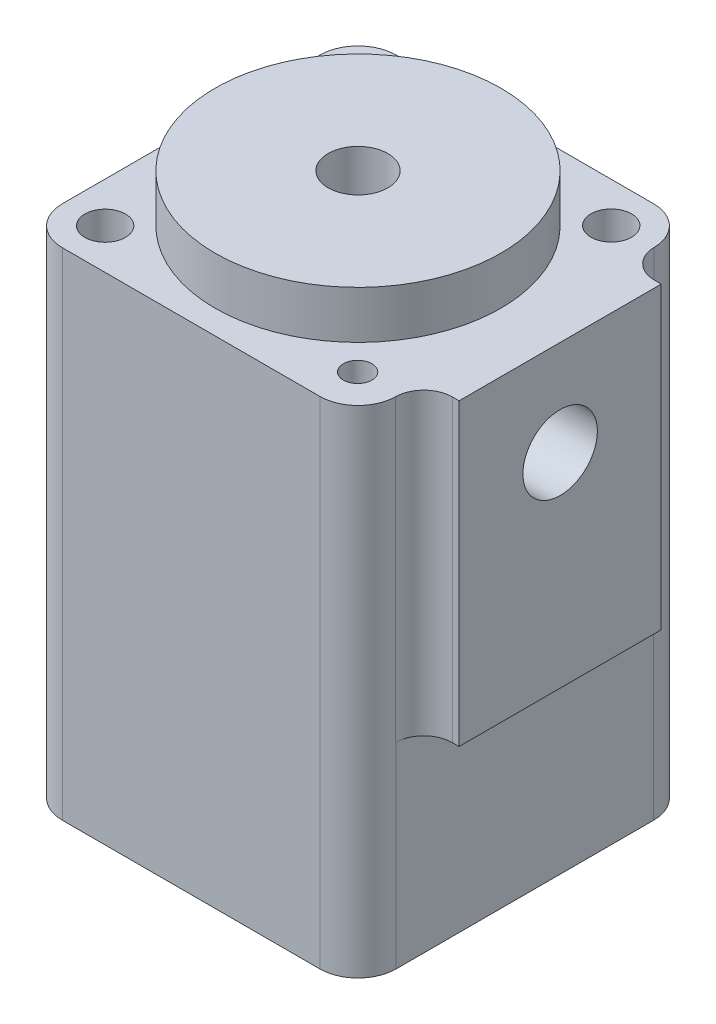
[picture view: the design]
ISO-10303-21;
HEADER;
FILE_DESCRIPTION(('STEP AP214'),'2;1');
FILE_NAME('part.step','',(''),(''),'','','');
FILE_SCHEMA(('AUTOMOTIVE_DESIGN { 1 0 10303 214 1 1 1 1 }'));
ENDSEC;
DATA;
#1=APPLICATION_CONTEXT('core data for automotive mechanical design processes');
#2=APPLICATION_PROTOCOL_DEFINITION('international standard','automotive_design',2000,#1);
#3=PRODUCT_CONTEXT('',#1,'mechanical');
#4=PRODUCT('Part','Part','',(#3));
#5=PRODUCT_RELATED_PRODUCT_CATEGORY('part','',(#4));
#6=PRODUCT_DEFINITION_FORMATION('','',#4);
#7=PRODUCT_DEFINITION_CONTEXT('part definition',#1,'design');
#8=PRODUCT_DEFINITION('design','',#6,#7);
#9=PRODUCT_DEFINITION_SHAPE('','',#8);
#10=(LENGTH_UNIT() NAMED_UNIT(*) SI_UNIT(.MILLI.,.METRE.));
#11=(NAMED_UNIT(*) PLANE_ANGLE_UNIT() SI_UNIT($,.RADIAN.));
#12=(NAMED_UNIT(*) SI_UNIT($,.STERADIAN.) SOLID_ANGLE_UNIT());
#13=UNCERTAINTY_MEASURE_WITH_UNIT(LENGTH_MEASURE(1.E-05),#10,'distance_accuracy_value','');
#14=(GEOMETRIC_REPRESENTATION_CONTEXT(3) GLOBAL_UNCERTAINTY_ASSIGNED_CONTEXT((#13)) GLOBAL_UNIT_ASSIGNED_CONTEXT((#10,
#11,#12)) REPRESENTATION_CONTEXT('',''));
#15=CARTESIAN_POINT('',(0.,0.,0.));
#16=DIRECTION('',(0.,0.,1.));
#17=DIRECTION('',(1.,0.,0.));
#18=AXIS2_PLACEMENT_3D('',#15,#16,#17);
#19=CARTESIAN_POINT('',(22.225,66.04,-22.225));
#20=DIRECTION('',(0.,-1.,0.));
#21=DIRECTION('',(0.,0.,-1.));
#22=AXIS2_PLACEMENT_3D('',#19,#20,#21);
#23=PLANE('',#22);
#24=CARTESIAN_POINT('',(16.8402,66.04,-16.8867242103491));
#25=DIRECTION('',(0.,1.,0.));
#26=DIRECTION('',(0.,0.,1.));
#27=AXIS2_PLACEMENT_3D('',#24,#25,#26);
#28=CIRCLE('',#27,2.70509999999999);
#29=CARTESIAN_POINT('',(16.8402,66.04,-14.1816242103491));
#30=VERTEX_POINT('',#29);
#31=EDGE_CURVE('E234',#30,#30,#28,.T.);
#32=ORIENTED_EDGE('',*,*,#31,.F.);
#33=EDGE_LOOP('',(#32));
#34=FACE_BOUND('',#33,.T.);
#35=CARTESIAN_POINT('',(-16.8402,66.04,16.8353752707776));
#36=DIRECTION('',(0.,1.,0.));
#37=DIRECTION('',(0.,0.,1.));
#38=AXIS2_PLACEMENT_3D('',#35,#36,#37);
#39=CIRCLE('',#38,2.70509999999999);
#40=CARTESIAN_POINT('',(-16.8402,66.04,19.5404752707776));
#41=VERTEX_POINT('',#40);
#42=EDGE_CURVE('E240',#41,#41,#39,.T.);
#43=ORIENTED_EDGE('',*,*,#42,.F.);
#44=EDGE_LOOP('',(#43));
#45=FACE_BOUND('',#44,.T.);
#46=CARTESIAN_POINT('',(-16.8402,66.04,-16.8353752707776));
#47=DIRECTION('',(0.,1.,0.));
#48=DIRECTION('',(0.,0.,1.));
#49=AXIS2_PLACEMENT_3D('',#46,#47,#48);
#50=CIRCLE('',#49,1.89864999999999);
#51=CARTESIAN_POINT('',(-16.8402,66.04,-14.9367252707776));
#52=VERTEX_POINT('',#51);
#53=EDGE_CURVE('E246',#52,#52,#50,.T.);
#54=ORIENTED_EDGE('',*,*,#53,.F.);
#55=EDGE_LOOP('',(#54));
#56=FACE_BOUND('',#55,.T.);
#57=CARTESIAN_POINT('',(16.8402,66.04,16.8867242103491));
#58=DIRECTION('',(0.,1.,0.));
#59=DIRECTION('',(0.,0.,1.));
#60=AXIS2_PLACEMENT_3D('',#57,#58,#59);
#61=CIRCLE('',#60,1.89864999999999);
#62=CARTESIAN_POINT('',(16.8402,66.04,18.7853742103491));
#63=VERTEX_POINT('',#62);
#64=EDGE_CURVE('E252',#63,#63,#61,.T.);
#65=ORIENTED_EDGE('',*,*,#64,.F.);
#66=EDGE_LOOP('',(#65));
#67=FACE_BOUND('',#66,.T.);
#68=DIRECTION('',(-1.,0.,0.));
#69=VECTOR('',#68,1.);
#70=CARTESIAN_POINT('',(-22.225,66.04,-22.225));
#71=LINE('',#70,#69);
#72=CARTESIAN_POINT('',(17.145,66.04,-22.225));
#73=VERTEX_POINT('',#72);
#74=CARTESIAN_POINT('',(-17.145,66.04,-22.225));
#75=VERTEX_POINT('',#74);
#76=EDGE_CURVE('E296',#73,#75,#71,.T.);
#77=ORIENTED_EDGE('',*,*,#76,.T.);
#78=CARTESIAN_POINT('',(-17.145,66.04,-17.145));
#79=DIRECTION('',(0.,-1.,0.));
#80=DIRECTION('',(0.,0.,-1.));
#81=AXIS2_PLACEMENT_3D('',#78,#79,#80);
#82=CIRCLE('',#81,5.08);
#83=CARTESIAN_POINT('',(-22.225,66.04,-17.145));
#84=VERTEX_POINT('',#83);
#85=EDGE_CURVE('E344',#75,#84,#82,.F.);
#86=ORIENTED_EDGE('',*,*,#85,.T.);
#87=DIRECTION('',(0.,0.,1.));
#88=VECTOR('',#87,1.);
#89=CARTESIAN_POINT('',(-22.225,66.04,22.225));
#90=LINE('',#89,#88);
#91=CARTESIAN_POINT('',(-22.225,66.04,17.145));
#92=VERTEX_POINT('',#91);
#93=EDGE_CURVE('E299',#84,#92,#90,.T.);
#94=ORIENTED_EDGE('',*,*,#93,.T.);
#95=CARTESIAN_POINT('',(-17.145,66.04,17.145));
#96=DIRECTION('',(0.,-1.,0.));
#97=DIRECTION('',(0.,0.,-1.));
#98=AXIS2_PLACEMENT_3D('',#95,#96,#97);
#99=CIRCLE('',#98,5.08);
#100=CARTESIAN_POINT('',(-17.145,66.04,22.225));
#101=VERTEX_POINT('',#100);
#102=EDGE_CURVE('E342',#92,#101,#99,.F.);
#103=ORIENTED_EDGE('',*,*,#102,.T.);
#104=DIRECTION('',(1.,0.,0.));
#105=VECTOR('',#104,1.);
#106=CARTESIAN_POINT('',(-22.225,66.04,22.225));
#107=LINE('',#106,#105);
#108=CARTESIAN_POINT('',(17.145,66.04,22.225));
#109=VERTEX_POINT('',#108);
#110=EDGE_CURVE('E303',#101,#109,#107,.T.);
#111=ORIENTED_EDGE('',*,*,#110,.T.);
#112=CARTESIAN_POINT('',(17.145,66.04,17.145));
#113=DIRECTION('',(0.,-1.,0.));
#114=DIRECTION('',(0.,0.,-1.));
#115=AXIS2_PLACEMENT_3D('',#112,#113,#114);
#116=CIRCLE('',#115,5.08);
#117=CARTESIAN_POINT('',(22.224481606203,66.04,17.2175714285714));
#118=VERTEX_POINT('',#117);
#119=EDGE_CURVE('E337',#109,#118,#116,.F.);
#120=ORIENTED_EDGE('',*,*,#119,.T.);
#121=CARTESIAN_POINT('',(26.0340928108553,66.04,17.272));
#122=DIRECTION('',(0.,-1.,0.));
#123=DIRECTION('',(0.,0.,-1.));
#124=AXIS2_PLACEMENT_3D('',#121,#122,#123);
#125=CIRCLE('',#124,3.81);
#126=CARTESIAN_POINT('',(26.0340928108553,66.04,13.462));
#127=VERTEX_POINT('',#126);
#128=EDGE_CURVE('E373',#118,#127,#125,.T.);
#129=ORIENTED_EDGE('',*,*,#128,.T.);
#130=DIRECTION('',(1.,0.,0.));
#131=VECTOR('',#130,1.);
#132=CARTESIAN_POINT('',(26.924,66.04,13.462));
#133=LINE('',#132,#131);
#134=CARTESIAN_POINT('',(26.924,66.04,13.462));
#135=VERTEX_POINT('',#134);
#136=EDGE_CURVE('E275',#127,#135,#133,.T.);
#137=ORIENTED_EDGE('',*,*,#136,.T.);
#138=DIRECTION('',(0.,0.,-1.));
#139=VECTOR('',#138,1.);
#140=CARTESIAN_POINT('',(26.924,66.04,-13.462));
#141=LINE('',#140,#139);
#142=CARTESIAN_POINT('',(26.924,66.04,-13.462));
#143=VERTEX_POINT('',#142);
#144=EDGE_CURVE('E277',#135,#143,#141,.T.);
#145=ORIENTED_EDGE('',*,*,#144,.T.);
#146=DIRECTION('',(-1.,0.,0.));
#147=VECTOR('',#146,1.);
#148=CARTESIAN_POINT('',(22.225,66.04,-13.462));
#149=LINE('',#148,#147);
#150=CARTESIAN_POINT('',(26.0340928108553,66.04,-13.462));
#151=VERTEX_POINT('',#150);
#152=EDGE_CURVE('E266',#143,#151,#149,.T.);
#153=ORIENTED_EDGE('',*,*,#152,.T.);
#154=CARTESIAN_POINT('',(26.0340928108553,66.04,-17.272));
#155=DIRECTION('',(0.,-1.,0.));
#156=DIRECTION('',(0.,0.,-1.));
#157=AXIS2_PLACEMENT_3D('',#154,#155,#156);
#158=CIRCLE('',#157,3.81);
#159=CARTESIAN_POINT('',(22.224481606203,66.04,-17.2175714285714));
#160=VERTEX_POINT('',#159);
#161=EDGE_CURVE('E377',#151,#160,#158,.T.);
#162=ORIENTED_EDGE('',*,*,#161,.T.);
#163=CARTESIAN_POINT('',(17.145,66.04,-17.145));
#164=DIRECTION('',(0.,-1.,0.));
#165=DIRECTION('',(0.,0.,-1.));
#166=AXIS2_PLACEMENT_3D('',#163,#164,#165);
#167=CIRCLE('',#166,5.08);
#168=EDGE_CURVE('E340',#160,#73,#167,.F.);
#169=ORIENTED_EDGE('',*,*,#168,.T.);
#170=EDGE_LOOP('',(#77,#86,#94,#103,#111,#120,#129,#137,#145,#153,#162,#169));
#171=FACE_BOUND('',#170,.T.);
#172=CARTESIAN_POINT('',(0.,66.04,0.));
#173=DIRECTION('',(0.,-1.,0.));
#174=DIRECTION('',(0.,0.,-1.));
#175=AXIS2_PLACEMENT_3D('',#172,#173,#174);
#176=CIRCLE('',#175,19.0373);
#177=CARTESIAN_POINT('',(0.,66.04,-19.0373));
#178=VERTEX_POINT('',#177);
#179=EDGE_CURVE('E306',#178,#178,#176,.F.);
#180=ORIENTED_EDGE('',*,*,#179,.F.);
#181=EDGE_LOOP('',(#180));
#182=FACE_BOUND('',#181,.T.);
#183=ADVANCED_FACE('F36',(#34,#45,#56,#67,#171,#182),#23,.F.);
#184=CARTESIAN_POINT('',(22.225,66.04,22.225));
#185=DIRECTION('',(-1.,0.,0.));
#186=DIRECTION('',(0.,0.,1.));
#187=AXIS2_PLACEMENT_3D('',#184,#185,#186);
#188=PLANE('',#187);
#189=DIRECTION('',(0.,0.,1.));
#190=VECTOR('',#189,1.);
#191=CARTESIAN_POINT('',(22.225,26.162,-13.462));
#192=LINE('',#191,#190);
#193=CARTESIAN_POINT('',(22.225,26.162,-17.145));
#194=VERTEX_POINT('',#193);
#195=CARTESIAN_POINT('',(22.225,26.162,17.145));
#196=VERTEX_POINT('',#195);
#197=EDGE_CURVE('E263',#194,#196,#192,.T.);
#198=ORIENTED_EDGE('',*,*,#197,.T.);
#199=DIRECTION('',(0.,-1.,0.));
#200=VECTOR('',#199,1.);
#201=CARTESIAN_POINT('',(22.225,66.04,17.145));
#202=LINE('',#201,#200);
#203=CARTESIAN_POINT('',(22.225,0.,17.145));
#204=VERTEX_POINT('',#203);
#205=EDGE_CURVE('E351',#196,#204,#202,.T.);
#206=ORIENTED_EDGE('',*,*,#205,.T.);
#207=DIRECTION('',(0.,0.,-1.));
#208=VECTOR('',#207,1.);
#209=CARTESIAN_POINT('',(22.225,0.,22.225));
#210=LINE('',#209,#208);
#211=CARTESIAN_POINT('',(22.225,0.,-17.145));
#212=VERTEX_POINT('',#211);
#213=EDGE_CURVE('E295',#204,#212,#210,.T.);
#214=ORIENTED_EDGE('',*,*,#213,.T.);
#215=DIRECTION('',(0.,-1.,0.));
#216=VECTOR('',#215,1.);
#217=CARTESIAN_POINT('',(22.225,66.04,-17.145));
#218=LINE('',#217,#216);
#219=EDGE_CURVE('E353',#212,#194,#218,.F.);
#220=ORIENTED_EDGE('',*,*,#219,.T.);
#221=EDGE_LOOP('',(#198,#206,#214,#220));
#222=FACE_BOUND('',#221,.T.);
#223=ADVANCED_FACE('F437',(#222),#188,.F.);
#224=CARTESIAN_POINT('',(-22.225,66.04,-22.225));
#225=DIRECTION('',(0.,0.,1.));
#226=DIRECTION('',(1.,0.,0.));
#227=AXIS2_PLACEMENT_3D('',#224,#225,#226);
#228=PLANE('',#227);
#229=DIRECTION('',(-1.,0.,0.));
#230=VECTOR('',#229,1.);
#231=CARTESIAN_POINT('',(-22.225,0.,-22.225));
#232=LINE('',#231,#230);
#233=CARTESIAN_POINT('',(17.145,0.,-22.225));
#234=VERTEX_POINT('',#233);
#235=CARTESIAN_POINT('',(-17.145,0.,-22.225));
#236=VERTEX_POINT('',#235);
#237=EDGE_CURVE('E309',#234,#236,#232,.T.);
#238=ORIENTED_EDGE('',*,*,#237,.T.);
#239=DIRECTION('',(0.,-1.,0.));
#240=VECTOR('',#239,1.);
#241=CARTESIAN_POINT('',(-17.145,66.04,-22.225));
#242=LINE('',#241,#240);
#243=EDGE_CURVE('E335',#236,#75,#242,.F.);
#244=ORIENTED_EDGE('',*,*,#243,.T.);
#245=ORIENTED_EDGE('',*,*,#76,.F.);
#246=DIRECTION('',(0.,-1.,0.));
#247=VECTOR('',#246,1.);
#248=CARTESIAN_POINT('',(17.145,66.04,-22.225));
#249=LINE('',#248,#247);
#250=EDGE_CURVE('E332',#73,#234,#249,.T.);
#251=ORIENTED_EDGE('',*,*,#250,.T.);
#252=EDGE_LOOP('',(#238,#244,#245,#251));
#253=FACE_BOUND('',#252,.T.);
#254=ADVANCED_FACE('F443',(#253),#228,.F.);
#255=CARTESIAN_POINT('',(-22.225,66.04,22.225));
#256=DIRECTION('',(1.,0.,0.));
#257=DIRECTION('',(0.,0.,-1.));
#258=AXIS2_PLACEMENT_3D('',#255,#256,#257);
#259=PLANE('',#258);
#260=ORIENTED_EDGE('',*,*,#93,.F.);
#261=DIRECTION('',(0.,-1.,0.));
#262=VECTOR('',#261,1.);
#263=CARTESIAN_POINT('',(-22.225,66.04,-17.145));
#264=LINE('',#263,#262);
#265=CARTESIAN_POINT('',(-22.225,0.,-17.145));
#266=VERTEX_POINT('',#265);
#267=EDGE_CURVE('E321',#84,#266,#264,.T.);
#268=ORIENTED_EDGE('',*,*,#267,.T.);
#269=DIRECTION('',(0.,0.,1.));
#270=VECTOR('',#269,1.);
#271=CARTESIAN_POINT('',(-22.225,0.,22.225));
#272=LINE('',#271,#270);
#273=CARTESIAN_POINT('',(-22.225,0.,17.145));
#274=VERTEX_POINT('',#273);
#275=EDGE_CURVE('E312',#266,#274,#272,.T.);
#276=ORIENTED_EDGE('',*,*,#275,.T.);
#277=DIRECTION('',(0.,-1.,0.));
#278=VECTOR('',#277,1.);
#279=CARTESIAN_POINT('',(-22.225,66.04,17.145));
#280=LINE('',#279,#278);
#281=EDGE_CURVE('E319',#274,#92,#280,.F.);
#282=ORIENTED_EDGE('',*,*,#281,.T.);
#283=EDGE_LOOP('',(#260,#268,#276,#282));
#284=FACE_BOUND('',#283,.T.);
#285=ADVANCED_FACE('F458',(#284),#259,.F.);
#286=CARTESIAN_POINT('',(-22.225,66.04,22.225));
#287=DIRECTION('',(0.,0.,-1.));
#288=DIRECTION('',(-1.,0.,0.));
#289=AXIS2_PLACEMENT_3D('',#286,#287,#288);
#290=PLANE('',#289);
#291=ORIENTED_EDGE('',*,*,#110,.F.);
#292=DIRECTION('',(0.,-1.,0.));
#293=VECTOR('',#292,1.);
#294=CARTESIAN_POINT('',(-17.145,66.04,22.225));
#295=LINE('',#294,#293);
#296=CARTESIAN_POINT('',(-17.145,0.,22.225));
#297=VERTEX_POINT('',#296);
#298=EDGE_CURVE('E348',#101,#297,#295,.T.);
#299=ORIENTED_EDGE('',*,*,#298,.T.);
#300=DIRECTION('',(1.,0.,0.));
#301=VECTOR('',#300,1.);
#302=CARTESIAN_POINT('',(-22.225,0.,22.225));
#303=LINE('',#302,#301);
#304=CARTESIAN_POINT('',(17.145,0.,22.225));
#305=VERTEX_POINT('',#304);
#306=EDGE_CURVE('E300',#297,#305,#303,.T.);
#307=ORIENTED_EDGE('',*,*,#306,.T.);
#308=DIRECTION('',(0.,-1.,0.));
#309=VECTOR('',#308,1.);
#310=CARTESIAN_POINT('',(17.145,66.04,22.225));
#311=LINE('',#310,#309);
#312=EDGE_CURVE('E346',#305,#109,#311,.F.);
#313=ORIENTED_EDGE('',*,*,#312,.T.);
#314=EDGE_LOOP('',(#291,#299,#307,#313));
#315=FACE_BOUND('',#314,.T.);
#316=ADVANCED_FACE('F454',(#315),#290,.F.);
#317=CARTESIAN_POINT('',(22.225,0.,-22.225));
#318=DIRECTION('',(0.,-1.,0.));
#319=DIRECTION('',(0.,0.,-1.));
#320=AXIS2_PLACEMENT_3D('',#317,#318,#319);
#321=PLANE('',#320);
#322=CARTESIAN_POINT('',(0.,0.,-9.525));
#323=DIRECTION('',(0.,-1.,0.));
#324=DIRECTION('',(0.,0.,-1.));
#325=AXIS2_PLACEMENT_3D('',#322,#323,#324);
#326=CIRCLE('',#325,10.5);
#327=CARTESIAN_POINT('',(-4.41863949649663,0.,0.));
#328=VERTEX_POINT('',#327);
#329=CARTESIAN_POINT('',(4.41863949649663,0.,0.));
#330=VERTEX_POINT('',#329);
#331=EDGE_CURVE('E200',#328,#330,#326,.T.);
#332=ORIENTED_EDGE('',*,*,#331,.F.);
#333=CARTESIAN_POINT('',(0.,0.,9.525));
#334=DIRECTION('',(0.,-1.,0.));
#335=DIRECTION('',(0.,0.,-1.));
#336=AXIS2_PLACEMENT_3D('',#333,#334,#335);
#337=CIRCLE('',#336,10.5);
#338=EDGE_CURVE('E231',#330,#328,#337,.T.);
#339=ORIENTED_EDGE('',*,*,#338,.F.);
#340=EDGE_LOOP('',(#332,#339));
#341=FACE_BOUND('',#340,.T.);
#342=CARTESIAN_POINT('',(16.8402,0.,-16.8867242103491));
#343=DIRECTION('',(0.,1.,0.));
#344=DIRECTION('',(0.,0.,1.));
#345=AXIS2_PLACEMENT_3D('',#342,#343,#344);
#346=CIRCLE('',#345,2.70509999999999);
#347=CARTESIAN_POINT('',(16.8402,0.,-14.1816242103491));
#348=VERTEX_POINT('',#347);
#349=EDGE_CURVE('E237',#348,#348,#346,.T.);
#350=ORIENTED_EDGE('',*,*,#349,.T.);
#351=EDGE_LOOP('',(#350));
#352=FACE_BOUND('',#351,.T.);
#353=CARTESIAN_POINT('',(-16.8402,0.,16.8353752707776));
#354=DIRECTION('',(0.,1.,0.));
#355=DIRECTION('',(0.,0.,1.));
#356=AXIS2_PLACEMENT_3D('',#353,#354,#355);
#357=CIRCLE('',#356,2.70509999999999);
#358=CARTESIAN_POINT('',(-16.8402,0.,19.5404752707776));
#359=VERTEX_POINT('',#358);
#360=EDGE_CURVE('E243',#359,#359,#357,.T.);
#361=ORIENTED_EDGE('',*,*,#360,.T.);
#362=EDGE_LOOP('',(#361));
#363=FACE_BOUND('',#362,.T.);
#364=CARTESIAN_POINT('',(-16.8402,0.,-16.8353752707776));
#365=DIRECTION('',(0.,1.,0.));
#366=DIRECTION('',(0.,0.,1.));
#367=AXIS2_PLACEMENT_3D('',#364,#365,#366);
#368=CIRCLE('',#367,1.89864999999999);
#369=CARTESIAN_POINT('',(-16.8402,0.,-14.9367252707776));
#370=VERTEX_POINT('',#369);
#371=EDGE_CURVE('E249',#370,#370,#368,.T.);
#372=ORIENTED_EDGE('',*,*,#371,.T.);
#373=EDGE_LOOP('',(#372));
#374=FACE_BOUND('',#373,.T.);
#375=CARTESIAN_POINT('',(16.8402,0.,16.8867242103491));
#376=DIRECTION('',(0.,1.,0.));
#377=DIRECTION('',(0.,0.,1.));
#378=AXIS2_PLACEMENT_3D('',#375,#376,#377);
#379=CIRCLE('',#378,1.89864999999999);
#380=CARTESIAN_POINT('',(16.8402,0.,18.7853742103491));
#381=VERTEX_POINT('',#380);
#382=EDGE_CURVE('E255',#381,#381,#379,.T.);
#383=ORIENTED_EDGE('',*,*,#382,.T.);
#384=EDGE_LOOP('',(#383));
#385=FACE_BOUND('',#384,.T.);
#386=ORIENTED_EDGE('',*,*,#275,.F.);
#387=CARTESIAN_POINT('',(-17.145,0.,-17.145));
#388=DIRECTION('',(0.,-1.,0.));
#389=DIRECTION('',(0.,0.,-1.));
#390=AXIS2_PLACEMENT_3D('',#387,#388,#389);
#391=CIRCLE('',#390,5.08);
#392=EDGE_CURVE('E330',#266,#236,#391,.T.);
#393=ORIENTED_EDGE('',*,*,#392,.T.);
#394=ORIENTED_EDGE('',*,*,#237,.F.);
#395=CARTESIAN_POINT('',(17.145,0.,-17.145));
#396=DIRECTION('',(0.,-1.,0.));
#397=DIRECTION('',(0.,0.,-1.));
#398=AXIS2_PLACEMENT_3D('',#395,#396,#397);
#399=CIRCLE('',#398,5.08);
#400=EDGE_CURVE('E326',#234,#212,#399,.T.);
#401=ORIENTED_EDGE('',*,*,#400,.T.);
#402=ORIENTED_EDGE('',*,*,#213,.F.);
#403=CARTESIAN_POINT('',(17.145,0.,17.145));
#404=DIRECTION('',(0.,-1.,0.));
#405=DIRECTION('',(0.,0.,-1.));
#406=AXIS2_PLACEMENT_3D('',#403,#404,#405);
#407=CIRCLE('',#406,5.08);
#408=EDGE_CURVE('E324',#204,#305,#407,.T.);
#409=ORIENTED_EDGE('',*,*,#408,.T.);
#410=ORIENTED_EDGE('',*,*,#306,.F.);
#411=CARTESIAN_POINT('',(-17.145,0.,17.145));
#412=DIRECTION('',(0.,-1.,0.));
#413=DIRECTION('',(0.,0.,-1.));
#414=AXIS2_PLACEMENT_3D('',#411,#412,#413);
#415=CIRCLE('',#414,5.08);
#416=EDGE_CURVE('E328',#297,#274,#415,.T.);
#417=ORIENTED_EDGE('',*,*,#416,.T.);
#418=EDGE_LOOP('',(#386,#393,#394,#401,#402,#409,#410,#417));
#419=FACE_BOUND('',#418,.T.);
#420=ADVANCED_FACE('F451',(#341,#352,#363,#374,#385,#419),#321,.T.);
#421=CARTESIAN_POINT('',(0.,72.39,0.));
#422=DIRECTION('',(0.,-1.,0.));
#423=DIRECTION('',(0.,0.,-1.));
#424=AXIS2_PLACEMENT_3D('',#421,#422,#423);
#425=CYLINDRICAL_SURFACE('',#424,19.0373);
#426=CARTESIAN_POINT('',(0.,72.39,0.));
#427=DIRECTION('',(0.,1.,0.));
#428=DIRECTION('',(0.,0.,1.));
#429=AXIS2_PLACEMENT_3D('',#426,#427,#428);
#430=CIRCLE('',#429,19.0373);
#431=CARTESIAN_POINT('',(0.,72.39,19.0373));
#432=VERTEX_POINT('',#431);
#433=EDGE_CURVE('E290',#432,#432,#430,.T.);
#434=ORIENTED_EDGE('',*,*,#433,.F.);
#435=EDGE_LOOP('',(#434));
#436=FACE_BOUND('',#435,.T.);
#437=ORIENTED_EDGE('',*,*,#179,.T.);
#438=EDGE_LOOP('',(#437));
#439=FACE_BOUND('',#438,.T.);
#440=ADVANCED_FACE('F450',(#436,#439),#425,.T.);
#441=CARTESIAN_POINT('',(0.,72.39,0.));
#442=DIRECTION('',(0.,1.,0.));
#443=DIRECTION('',(0.,0.,1.));
#444=AXIS2_PLACEMENT_3D('',#441,#442,#443);
#445=PLANE('',#444);
#446=CARTESIAN_POINT('',(0.,72.39,0.));
#447=DIRECTION('',(0.,1.,0.));
#448=DIRECTION('',(0.,0.,1.));
#449=AXIS2_PLACEMENT_3D('',#446,#447,#448);
#450=CIRCLE('',#449,3.96875);
#451=CARTESIAN_POINT('',(0.,72.39,3.96875));
#452=VERTEX_POINT('',#451);
#453=EDGE_CURVE('E284',#452,#452,#450,.T.);
#454=ORIENTED_EDGE('',*,*,#453,.F.);
#455=EDGE_LOOP('',(#454));
#456=FACE_BOUND('',#455,.T.);
#457=ORIENTED_EDGE('',*,*,#433,.T.);
#458=EDGE_LOOP('',(#457));
#459=FACE_BOUND('',#458,.T.);
#460=ADVANCED_FACE('F434',(#456,#459),#445,.T.);
#461=CARTESIAN_POINT('',(0.,34.29,0.));
#462=DIRECTION('',(0.,1.,0.));
#463=DIRECTION('',(0.,0.,1.));
#464=AXIS2_PLACEMENT_3D('',#461,#462,#463);
#465=CYLINDRICAL_SURFACE('',#464,3.96875);
#466=DIRECTION('',(0.,1.,0.));
#467=VECTOR('',#466,1.);
#468=CARTESIAN_POINT('',(0.761999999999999,34.29,-3.89491111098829));
#469=LINE('',#468,#467);
#470=CARTESIAN_POINT('',(0.761999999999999,50.2679618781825,-3.89491111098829));
#471=VERTEX_POINT('',#470);
#472=CARTESIAN_POINT('',(0.761999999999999,56.4120381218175,-3.89491111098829));
#473=VERTEX_POINT('',#472);
#474=EDGE_CURVE('E387',#471,#473,#469,.T.);
#475=ORIENTED_EDGE('',*,*,#474,.T.);
#476=CARTESIAN_POINT('',(0.761999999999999,56.4120381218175,-3.89491111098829));
#477=CARTESIAN_POINT('',(0.872602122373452,56.4394920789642,-3.87326278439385));
#478=CARTESIAN_POINT('',(0.980867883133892,56.4719380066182,-3.84720182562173));
#479=CARTESIAN_POINT('',(1.19218803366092,56.5444070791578,-3.78704563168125));
#480=CARTESIAN_POINT('',(1.29525636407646,56.5844084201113,-3.75297344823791));
#481=CARTESIAN_POINT('',(1.49566621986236,56.6695055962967,-3.67768316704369));
#482=CARTESIAN_POINT('',(1.5930386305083,56.7145691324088,-3.63650956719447));
#483=CARTESIAN_POINT('',(1.78287873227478,56.808231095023,-3.54729779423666));
#484=CARTESIAN_POINT('',(1.87534246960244,56.8568322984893,-3.49925419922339));
#485=CARTESIAN_POINT('',(2.14346593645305,57.0045588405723,-3.34643132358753));
#486=CARTESIAN_POINT('',(2.31214160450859,57.1066517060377,-3.2320830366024));
#487=CARTESIAN_POINT('',(2.63072429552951,57.3102094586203,-2.97855163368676));
#488=CARTESIAN_POINT('',(2.78058879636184,57.4116724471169,-2.83931391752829));
#489=CARTESIAN_POINT('',(3.06070716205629,57.6078620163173,-2.53499263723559));
#490=CARTESIAN_POINT('',(3.19076478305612,57.7025168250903,-2.36967981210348));
#491=CARTESIAN_POINT('',(3.4256245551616,57.8771294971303,-2.01521458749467));
#492=CARTESIAN_POINT('',(3.53047206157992,57.9571136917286,-1.82610594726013));
#493=CARTESIAN_POINT('',(3.69375347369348,58.0832505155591,-1.4626661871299));
#494=CARTESIAN_POINT('',(3.75714272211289,58.1329001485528,-1.2917896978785));
#495=CARTESIAN_POINT('',(3.86044559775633,58.2142994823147,-0.938962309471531));
#496=CARTESIAN_POINT('',(3.90037223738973,58.2460591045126,-0.757017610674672));
#497=CARTESIAN_POINT('',(3.95439235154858,58.2891133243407,-0.386039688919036));
#498=CARTESIAN_POINT('',(3.96836910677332,58.3003154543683,-0.196978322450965));
#499=CARTESIAN_POINT('',(3.96911526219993,58.3009120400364,0.181225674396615));
#500=CARTESIAN_POINT('',(3.95588783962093,58.2903090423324,0.370368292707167));
#501=CARTESIAN_POINT('',(3.9051423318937,58.2498577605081,0.728854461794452));
#502=CARTESIAN_POINT('',(3.86946961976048,58.2214722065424,0.898634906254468));
#503=CARTESIAN_POINT('',(3.7775713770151,58.1489525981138,1.22896239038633));
#504=CARTESIAN_POINT('',(3.72134037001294,58.1048143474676,1.38950695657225));
#505=CARTESIAN_POINT('',(3.5858484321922,57.999733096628,1.71034193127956));
#506=CARTESIAN_POINT('',(3.50516429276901,57.9377694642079,1.86968958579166));
#507=CARTESIAN_POINT('',(3.32589301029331,57.802608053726,2.17265656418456));
#508=CARTESIAN_POINT('',(3.22730049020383,57.7294069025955,2.31627114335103));
#509=CARTESIAN_POINT('',(2.99373860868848,57.5603667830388,2.61361058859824));
#510=CARTESIAN_POINT('',(2.8554280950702,57.4629059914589,2.76377649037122));
#511=CARTESIAN_POINT('',(2.5590236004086,57.2634213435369,3.04032718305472));
#512=CARTESIAN_POINT('',(2.40088918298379,57.1613884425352,3.16666200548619));
#513=CARTESIAN_POINT('',(2.15139891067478,57.0116523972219,3.33651112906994));
#514=CARTESIAN_POINT('',(2.0670390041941,56.9627389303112,3.38944204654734));
#515=CARTESIAN_POINT('',(1.89374016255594,56.8667273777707,3.48923040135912));
#516=CARTESIAN_POINT('',(1.80480006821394,56.8196297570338,3.53608629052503));
#517=CARTESIAN_POINT('',(1.62270487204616,56.7287679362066,3.62325141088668));
#518=CARTESIAN_POINT('',(1.52957009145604,56.684989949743,3.66358860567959));
#519=CARTESIAN_POINT('',(1.33867874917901,56.6021235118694,3.73756365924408));
#520=CARTESIAN_POINT('',(1.24092477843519,56.563032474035,3.77120521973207));
#521=CARTESIAN_POINT('',(1.07945788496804,56.5052356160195,3.81966782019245));
#522=CARTESIAN_POINT('',(1.01715104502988,56.4844810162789,3.8367444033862));
#523=CARTESIAN_POINT('',(0.890820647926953,56.4459151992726,3.86803010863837));
#524=CARTESIAN_POINT('',(0.826794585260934,56.428108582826,3.88223475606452));
#525=CARTESIAN_POINT('',(0.761999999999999,56.4120381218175,3.89491111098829));
#526=B_SPLINE_CURVE_WITH_KNOTS('',3,(#476,#477,#478,#479,#480,#481,#482,#483,#484,#485,#486,
#487,#488,#489,#490,#491,#492,#493,#494,#495,#496,#497,#498,#499,#500,#501,#502,#503,#504,#505,
#506,#507,#508,#509,#510,#511,#512,#513,#514,#515,#516,#517,#518,#519,#520,#521,#522,#523,#524,
#525),.UNSPECIFIED.,.F.,.F.,(4,2,2,2,2,2,2,2,2,2,2,2,2,2,2,2,2,2,2,2,2,2,2,2,4),(0.,
0.34745550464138,0.693923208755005,1.0382939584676,1.38293800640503,2.06432483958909,
2.7472252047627,3.43650407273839,4.12453342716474,4.68887944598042,5.25291218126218,
5.819475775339,6.38597320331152,6.91108033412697,7.43632744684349,8.00141087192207,
8.56666424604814,9.24299422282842,9.92072692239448,10.2533741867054,10.5861060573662,
10.9173703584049,11.2484510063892,11.451886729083,11.6556370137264),.UNSPECIFIED.);
#527=CARTESIAN_POINT('',(0.761999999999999,56.4120381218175,3.89491111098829));
#528=VERTEX_POINT('',#527);
#529=EDGE_CURVE('E11',#473,#528,#526,.T.);
#530=ORIENTED_EDGE('',*,*,#529,.T.);
#531=DIRECTION('',(0.,1.,0.));
#532=VECTOR('',#531,1.);
#533=CARTESIAN_POINT('',(0.761999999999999,34.29,3.89491111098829));
#534=LINE('',#533,#532);
#535=CARTESIAN_POINT('',(0.761999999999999,50.2679618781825,3.89491111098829));
#536=VERTEX_POINT('',#535);
#537=EDGE_CURVE('E49',#528,#536,#534,.F.);
#538=ORIENTED_EDGE('',*,*,#537,.T.);
#539=CARTESIAN_POINT('',(0.761999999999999,50.2679618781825,3.89491111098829));
#540=CARTESIAN_POINT('',(0.872602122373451,50.2405079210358,3.87326278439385));
#541=CARTESIAN_POINT('',(0.98086788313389,50.2080619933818,3.84720182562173));
#542=CARTESIAN_POINT('',(1.19218803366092,50.1355929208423,3.78704563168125));
#543=CARTESIAN_POINT('',(1.29525636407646,50.0955915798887,3.75297344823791));
#544=CARTESIAN_POINT('',(1.49566621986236,50.0104944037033,3.6776831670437));
#545=CARTESIAN_POINT('',(1.5930386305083,49.9654308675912,3.63650956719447));
#546=CARTESIAN_POINT('',(1.78287873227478,49.871768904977,3.54729779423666));
#547=CARTESIAN_POINT('',(1.87534246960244,49.8231677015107,3.49925419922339));
#548=CARTESIAN_POINT('',(2.14346593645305,49.6754411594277,3.34643132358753));
#549=CARTESIAN_POINT('',(2.31214160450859,49.5733482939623,3.2320830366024));
#550=CARTESIAN_POINT('',(2.63072429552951,49.3697905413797,2.97855163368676));
#551=CARTESIAN_POINT('',(2.78058879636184,49.2683275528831,2.83931391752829));
#552=CARTESIAN_POINT('',(3.06070716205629,49.0721379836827,2.5349926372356));
#553=CARTESIAN_POINT('',(3.19076478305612,48.9774831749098,2.36967981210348));
#554=CARTESIAN_POINT('',(3.42562455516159,48.8028705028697,2.01521458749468));
#555=CARTESIAN_POINT('',(3.53047206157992,48.7228863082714,1.82610594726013));
#556=CARTESIAN_POINT('',(3.69375347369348,48.5967494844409,1.46266618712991));
#557=CARTESIAN_POINT('',(3.75714272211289,48.5470998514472,1.29178969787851));
#558=CARTESIAN_POINT('',(3.86044559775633,48.4657005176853,0.938962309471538));
#559=CARTESIAN_POINT('',(3.90037223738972,48.4339408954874,0.757017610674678));
#560=CARTESIAN_POINT('',(3.95439235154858,48.3908866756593,0.386039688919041));
#561=CARTESIAN_POINT('',(3.96836910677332,48.3796845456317,0.19697832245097));
#562=CARTESIAN_POINT('',(3.96911526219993,48.3790879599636,-0.18122567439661));
#563=CARTESIAN_POINT('',(3.95588783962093,48.3896909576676,-0.370368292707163));
#564=CARTESIAN_POINT('',(3.9051423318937,48.4301422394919,-0.728854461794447));
#565=CARTESIAN_POINT('',(3.86946961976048,48.4585277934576,-0.898634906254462));
#566=CARTESIAN_POINT('',(3.7775713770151,48.5310474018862,-1.22896239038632));
#567=CARTESIAN_POINT('',(3.72134037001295,48.5751856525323,-1.38950695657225));
#568=CARTESIAN_POINT('',(3.5858484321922,48.680266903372,-1.71034193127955));
#569=CARTESIAN_POINT('',(3.50516429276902,48.7422305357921,-1.86968958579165));
#570=CARTESIAN_POINT('',(3.32589301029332,48.877391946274,-2.17265656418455));
#571=CARTESIAN_POINT('',(3.22730049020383,48.9505930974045,-2.31627114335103));
#572=CARTESIAN_POINT('',(2.99373860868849,49.1196332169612,-2.61361058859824));
#573=CARTESIAN_POINT('',(2.85542809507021,49.2170940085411,-2.76377649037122));
#574=CARTESIAN_POINT('',(2.5590236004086,49.4165786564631,-3.04032718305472));
#575=CARTESIAN_POINT('',(2.4008891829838,49.5186115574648,-3.16666200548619));
#576=CARTESIAN_POINT('',(2.15139891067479,49.6683476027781,-3.33651112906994));
#577=CARTESIAN_POINT('',(2.0670390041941,49.7172610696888,-3.38944204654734));
#578=CARTESIAN_POINT('',(1.89374016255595,49.8132726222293,-3.48923040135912));
#579=CARTESIAN_POINT('',(1.80480006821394,49.8603702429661,-3.53608629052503));
#580=CARTESIAN_POINT('',(1.62270487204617,49.9512320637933,-3.62325141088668));
#581=CARTESIAN_POINT('',(1.52957009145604,49.995010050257,-3.66358860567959));
#582=CARTESIAN_POINT('',(1.33867874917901,50.0778764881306,-3.73756365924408));
#583=CARTESIAN_POINT('',(1.2409247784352,50.116967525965,-3.77120521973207));
#584=CARTESIAN_POINT('',(1.07945788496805,50.1747643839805,-3.81966782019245));
#585=CARTESIAN_POINT('',(1.01715104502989,50.1955189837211,-3.83674440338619));
#586=CARTESIAN_POINT('',(0.890820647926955,50.2340848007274,-3.86803010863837));
#587=CARTESIAN_POINT('',(0.826794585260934,50.251891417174,-3.88223475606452));
#588=CARTESIAN_POINT('',(0.761999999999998,50.2679618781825,-3.89491111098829));
#589=B_SPLINE_CURVE_WITH_KNOTS('',3,(#539,#540,#541,#542,#543,#544,#545,#546,#547,#548,#549,
#550,#551,#552,#553,#554,#555,#556,#557,#558,#559,#560,#561,#562,#563,#564,#565,#566,#567,#568,
#569,#570,#571,#572,#573,#574,#575,#576,#577,#578,#579,#580,#581,#582,#583,#584,#585,#586,#587,
#588),.UNSPECIFIED.,.F.,.F.,(4,2,2,2,2,2,2,2,2,2,2,2,2,2,2,2,2,2,2,2,2,2,2,2,4),(0.,
0.347455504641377,0.693923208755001,1.03829395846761,1.38293800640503,2.06432483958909,
2.7472252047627,3.43650407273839,4.12453342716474,4.68887944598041,5.25291218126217,
5.819475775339,6.38597320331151,6.91108033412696,7.43632744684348,8.00141087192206,
8.56666424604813,9.24299422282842,9.92072692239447,10.2533741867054,10.5861060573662,
10.9173703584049,11.2484510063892,11.451886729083,11.6556370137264),.UNSPECIFIED.);
#590=EDGE_CURVE('E381',#536,#471,#589,.T.);
#591=ORIENTED_EDGE('',*,*,#590,.T.);
#592=EDGE_LOOP('',(#475,#530,#538,#591));
#593=FACE_BOUND('',#592,.T.);
#594=CARTESIAN_POINT('',(0.,34.29,0.));
#595=DIRECTION('',(0.,1.,0.));
#596=DIRECTION('',(0.,0.,1.));
#597=AXIS2_PLACEMENT_3D('',#594,#595,#596);
#598=CIRCLE('',#597,3.96875);
#599=CARTESIAN_POINT('',(0.,34.29,3.96875));
#600=VERTEX_POINT('',#599);
#601=EDGE_CURVE('E287',#600,#600,#598,.T.);
#602=ORIENTED_EDGE('',*,*,#601,.F.);
#603=EDGE_LOOP('',(#602));
#604=FACE_BOUND('',#603,.T.);
#605=ORIENTED_EDGE('',*,*,#453,.T.);
#606=EDGE_LOOP('',(#605));
#607=FACE_BOUND('',#606,.T.);
#608=ADVANCED_FACE('F388',(#593,#604,#607),#465,.F.);
#609=CARTESIAN_POINT('',(0.,34.29,0.));
#610=DIRECTION('',(0.,1.,0.));
#611=DIRECTION('',(0.,0.,1.));
#612=AXIS2_PLACEMENT_3D('',#609,#610,#611);
#613=PLANE('',#612);
#614=ORIENTED_EDGE('',*,*,#601,.T.);
#615=EDGE_LOOP('',(#614));
#616=FACE_BOUND('',#615,.T.);
#617=ADVANCED_FACE('F423',(#616),#613,.T.);
#618=CARTESIAN_POINT('',(-17.145,66.04,-17.145));
#619=DIRECTION('',(0.,-1.,0.));
#620=DIRECTION('',(0.,0.,-1.));
#621=AXIS2_PLACEMENT_3D('',#618,#619,#620);
#622=CYLINDRICAL_SURFACE('',#621,5.08);
#623=ORIENTED_EDGE('',*,*,#85,.F.);
#624=ORIENTED_EDGE('',*,*,#243,.F.);
#625=ORIENTED_EDGE('',*,*,#392,.F.);
#626=ORIENTED_EDGE('',*,*,#267,.F.);
#627=EDGE_LOOP('',(#623,#624,#625,#626));
#628=FACE_BOUND('',#627,.T.);
#629=ADVANCED_FACE('F425',(#628),#622,.T.);
#630=CARTESIAN_POINT('',(-17.145,66.04,17.145));
#631=DIRECTION('',(0.,-1.,0.));
#632=DIRECTION('',(0.,0.,-1.));
#633=AXIS2_PLACEMENT_3D('',#630,#631,#632);
#634=CYLINDRICAL_SURFACE('',#633,5.08);
#635=ORIENTED_EDGE('',*,*,#102,.F.);
#636=ORIENTED_EDGE('',*,*,#281,.F.);
#637=ORIENTED_EDGE('',*,*,#416,.F.);
#638=ORIENTED_EDGE('',*,*,#298,.F.);
#639=EDGE_LOOP('',(#635,#636,#637,#638));
#640=FACE_BOUND('',#639,.T.);
#641=ADVANCED_FACE('F431',(#640),#634,.T.);
#642=CARTESIAN_POINT('',(17.145,66.04,-17.145));
#643=DIRECTION('',(0.,-1.,0.));
#644=DIRECTION('',(0.,0.,-1.));
#645=AXIS2_PLACEMENT_3D('',#642,#643,#644);
#646=CYLINDRICAL_SURFACE('',#645,5.08);
#647=ORIENTED_EDGE('',*,*,#168,.F.);
#648=DIRECTION('',(0.,-1.,0.));
#649=VECTOR('',#648,1.);
#650=CARTESIAN_POINT('',(22.224481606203,66.04,-17.2175714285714));
#651=LINE('',#650,#649);
#652=CARTESIAN_POINT('',(22.224481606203,26.162,-17.2175714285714));
#653=VERTEX_POINT('',#652);
#654=EDGE_CURVE('E370',#160,#653,#651,.T.);
#655=ORIENTED_EDGE('',*,*,#654,.T.);
#656=CARTESIAN_POINT('',(17.145,26.162,-17.145));
#657=DIRECTION('',(0.,-1.,0.));
#658=DIRECTION('',(0.,0.,-1.));
#659=AXIS2_PLACEMENT_3D('',#656,#657,#658);
#660=CIRCLE('',#659,5.08);
#661=EDGE_CURVE('E367',#653,#194,#660,.T.);
#662=ORIENTED_EDGE('',*,*,#661,.T.);
#663=ORIENTED_EDGE('',*,*,#219,.F.);
#664=ORIENTED_EDGE('',*,*,#400,.F.);
#665=ORIENTED_EDGE('',*,*,#250,.F.);
#666=EDGE_LOOP('',(#647,#655,#662,#663,#664,#665));
#667=FACE_BOUND('',#666,.T.);
#668=ADVANCED_FACE('F468',(#667),#646,.T.);
#669=CARTESIAN_POINT('',(17.145,66.04,17.145));
#670=DIRECTION('',(0.,-1.,0.));
#671=DIRECTION('',(0.,0.,-1.));
#672=AXIS2_PLACEMENT_3D('',#669,#670,#671);
#673=CYLINDRICAL_SURFACE('',#672,5.08);
#674=CARTESIAN_POINT('',(17.145,26.162,17.145));
#675=DIRECTION('',(0.,-1.,0.));
#676=DIRECTION('',(0.,0.,-1.));
#677=AXIS2_PLACEMENT_3D('',#674,#675,#676);
#678=CIRCLE('',#677,5.08);
#679=CARTESIAN_POINT('',(22.224481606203,26.162,17.2175714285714));
#680=VERTEX_POINT('',#679);
#681=EDGE_CURVE('E356',#196,#680,#678,.T.);
#682=ORIENTED_EDGE('',*,*,#681,.T.);
#683=DIRECTION('',(0.,-1.,0.));
#684=VECTOR('',#683,1.);
#685=CARTESIAN_POINT('',(22.224481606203,66.04,17.2175714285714));
#686=LINE('',#685,#684);
#687=EDGE_CURVE('E359',#680,#118,#686,.F.);
#688=ORIENTED_EDGE('',*,*,#687,.T.);
#689=ORIENTED_EDGE('',*,*,#119,.F.);
#690=ORIENTED_EDGE('',*,*,#312,.F.);
#691=ORIENTED_EDGE('',*,*,#408,.F.);
#692=ORIENTED_EDGE('',*,*,#205,.F.);
#693=EDGE_LOOP('',(#682,#688,#689,#690,#691,#692));
#694=FACE_BOUND('',#693,.T.);
#695=ADVANCED_FACE('F416',(#694),#673,.T.);
#696=CARTESIAN_POINT('',(22.225,26.162,-13.462));
#697=DIRECTION('',(0.,0.,-1.));
#698=DIRECTION('',(-1.,0.,0.));
#699=AXIS2_PLACEMENT_3D('',#696,#697,#698);
#700=PLANE('',#699);
#701=DIRECTION('',(-1.,0.,0.));
#702=VECTOR('',#701,1.);
#703=CARTESIAN_POINT('',(22.225,26.162,-13.462));
#704=LINE('',#703,#702);
#705=CARTESIAN_POINT('',(26.924,26.162,-13.462));
#706=VERTEX_POINT('',#705);
#707=CARTESIAN_POINT('',(26.0340928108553,26.162,-13.462));
#708=VERTEX_POINT('',#707);
#709=EDGE_CURVE('E271',#706,#708,#704,.T.);
#710=ORIENTED_EDGE('',*,*,#709,.T.);
#711=DIRECTION('',(0.,1.,0.));
#712=VECTOR('',#711,1.);
#713=CARTESIAN_POINT('',(26.0340928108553,66.04,-13.462));
#714=LINE('',#713,#712);
#715=EDGE_CURVE('E364',#708,#151,#714,.T.);
#716=ORIENTED_EDGE('',*,*,#715,.T.);
#717=ORIENTED_EDGE('',*,*,#152,.F.);
#718=DIRECTION('',(0.,1.,0.));
#719=VECTOR('',#718,1.);
#720=CARTESIAN_POINT('',(26.924,26.162,-13.462));
#721=LINE('',#720,#719);
#722=EDGE_CURVE('E282',#706,#143,#721,.T.);
#723=ORIENTED_EDGE('',*,*,#722,.F.);
#724=EDGE_LOOP('',(#710,#716,#717,#723));
#725=FACE_BOUND('',#724,.T.);
#726=ADVANCED_FACE('F412',(#725),#700,.T.);
#727=CARTESIAN_POINT('',(26.924,26.162,-13.462));
#728=DIRECTION('',(1.,0.,0.));
#729=DIRECTION('',(0.,0.,-1.));
#730=AXIS2_PLACEMENT_3D('',#727,#728,#729);
#731=PLANE('',#730);
#732=CARTESIAN_POINT('',(26.924,53.34,0.));
#733=DIRECTION('',(1.,0.,0.));
#734=DIRECTION('',(0.,0.,-1.));
#735=AXIS2_PLACEMENT_3D('',#732,#733,#734);
#736=CIRCLE('',#735,4.96061999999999);
#737=CARTESIAN_POINT('',(26.924,53.34,-4.96061999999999));
#738=VERTEX_POINT('',#737);
#739=EDGE_CURVE('E258',#738,#738,#736,.T.);
#740=ORIENTED_EDGE('',*,*,#739,.F.);
#741=EDGE_LOOP('',(#740));
#742=FACE_BOUND('',#741,.T.);
#743=ORIENTED_EDGE('',*,*,#144,.F.);
#744=DIRECTION('',(0.,1.,0.));
#745=VECTOR('',#744,1.);
#746=CARTESIAN_POINT('',(26.924,26.162,13.462));
#747=LINE('',#746,#745);
#748=CARTESIAN_POINT('',(26.924,26.162,13.462));
#749=VERTEX_POINT('',#748);
#750=EDGE_CURVE('E274',#749,#135,#747,.T.);
#751=ORIENTED_EDGE('',*,*,#750,.F.);
#752=DIRECTION('',(0.,0.,-1.));
#753=VECTOR('',#752,1.);
#754=CARTESIAN_POINT('',(26.924,26.162,-13.462));
#755=LINE('',#754,#753);
#756=EDGE_CURVE('E268',#749,#706,#755,.T.);
#757=ORIENTED_EDGE('',*,*,#756,.T.);
#758=ORIENTED_EDGE('',*,*,#722,.T.);
#759=EDGE_LOOP('',(#743,#751,#757,#758));
#760=FACE_BOUND('',#759,.T.);
#761=ADVANCED_FACE('F415',(#742,#760),#731,.T.);
#762=CARTESIAN_POINT('',(26.924,26.162,13.462));
#763=DIRECTION('',(0.,0.,1.));
#764=DIRECTION('',(1.,0.,0.));
#765=AXIS2_PLACEMENT_3D('',#762,#763,#764);
#766=PLANE('',#765);
#767=ORIENTED_EDGE('',*,*,#136,.F.);
#768=DIRECTION('',(0.,1.,0.));
#769=VECTOR('',#768,1.);
#770=CARTESIAN_POINT('',(26.0340928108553,26.162,13.462));
#771=LINE('',#770,#769);
#772=CARTESIAN_POINT('',(26.0340928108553,26.162,13.462));
#773=VERTEX_POINT('',#772);
#774=EDGE_CURVE('E362',#127,#773,#771,.F.);
#775=ORIENTED_EDGE('',*,*,#774,.T.);
#776=DIRECTION('',(1.,0.,0.));
#777=VECTOR('',#776,1.);
#778=CARTESIAN_POINT('',(26.924,26.162,13.462));
#779=LINE('',#778,#777);
#780=EDGE_CURVE('E265',#773,#749,#779,.T.);
#781=ORIENTED_EDGE('',*,*,#780,.T.);
#782=ORIENTED_EDGE('',*,*,#750,.T.);
#783=EDGE_LOOP('',(#767,#775,#781,#782));
#784=FACE_BOUND('',#783,.T.);
#785=ADVANCED_FACE('F410',(#784),#766,.T.);
#786=CARTESIAN_POINT('',(22.225,26.162,13.462));
#787=DIRECTION('',(0.,-1.,0.));
#788=DIRECTION('',(0.,0.,-1.));
#789=AXIS2_PLACEMENT_3D('',#786,#787,#788);
#790=PLANE('',#789);
#791=ORIENTED_EDGE('',*,*,#197,.F.);
#792=ORIENTED_EDGE('',*,*,#661,.F.);
#793=CARTESIAN_POINT('',(26.0340928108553,26.162,-17.272));
#794=DIRECTION('',(0.,-1.,0.));
#795=DIRECTION('',(0.,0.,-1.));
#796=AXIS2_PLACEMENT_3D('',#793,#794,#795);
#797=CIRCLE('',#796,3.81);
#798=EDGE_CURVE('E379',#653,#708,#797,.F.);
#799=ORIENTED_EDGE('',*,*,#798,.T.);
#800=ORIENTED_EDGE('',*,*,#709,.F.);
#801=ORIENTED_EDGE('',*,*,#756,.F.);
#802=ORIENTED_EDGE('',*,*,#780,.F.);
#803=CARTESIAN_POINT('',(26.0340928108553,26.162,17.272));
#804=DIRECTION('',(0.,-1.,0.));
#805=DIRECTION('',(0.,0.,-1.));
#806=AXIS2_PLACEMENT_3D('',#803,#804,#805);
#807=CIRCLE('',#806,3.81);
#808=EDGE_CURVE('E375',#773,#680,#807,.F.);
#809=ORIENTED_EDGE('',*,*,#808,.T.);
#810=ORIENTED_EDGE('',*,*,#681,.F.);
#811=EDGE_LOOP('',(#791,#792,#799,#800,#801,#802,#809,#810));
#812=FACE_BOUND('',#811,.T.);
#813=ADVANCED_FACE('F406',(#812),#790,.T.);
#814=CARTESIAN_POINT('',(26.0340928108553,66.04,17.272));
#815=DIRECTION('',(0.,-1.,0.));
#816=DIRECTION('',(0.,0.,-1.));
#817=AXIS2_PLACEMENT_3D('',#814,#815,#816);
#818=CYLINDRICAL_SURFACE('',#817,3.81);
#819=ORIENTED_EDGE('',*,*,#808,.F.);
#820=ORIENTED_EDGE('',*,*,#774,.F.);
#821=ORIENTED_EDGE('',*,*,#128,.F.);
#822=ORIENTED_EDGE('',*,*,#687,.F.);
#823=EDGE_LOOP('',(#819,#820,#821,#822));
#824=FACE_BOUND('',#823,.T.);
#825=ADVANCED_FACE('F409',(#824),#818,.F.);
#826=CARTESIAN_POINT('',(26.0340928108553,66.04,-17.272));
#827=DIRECTION('',(0.,-1.,0.));
#828=DIRECTION('',(0.,0.,-1.));
#829=AXIS2_PLACEMENT_3D('',#826,#827,#828);
#830=CYLINDRICAL_SURFACE('',#829,3.81);
#831=ORIENTED_EDGE('',*,*,#798,.F.);
#832=ORIENTED_EDGE('',*,*,#654,.F.);
#833=ORIENTED_EDGE('',*,*,#161,.F.);
#834=ORIENTED_EDGE('',*,*,#715,.F.);
#835=EDGE_LOOP('',(#831,#832,#833,#834));
#836=FACE_BOUND('',#835,.T.);
#837=ADVANCED_FACE('F38',(#836),#830,.F.);
#838=CARTESIAN_POINT('',(0.761999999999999,53.34,0.));
#839=DIRECTION('',(-1.,0.,0.));
#840=DIRECTION('',(0.,0.,1.));
#841=AXIS2_PLACEMENT_3D('',#838,#839,#840);
#842=PLANE('',#841);
#843=CARTESIAN_POINT('',(0.761999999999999,53.34,0.));
#844=DIRECTION('',(1.,0.,0.));
#845=DIRECTION('',(0.,0.,-1.));
#846=AXIS2_PLACEMENT_3D('',#843,#844,#845);
#847=CIRCLE('',#846,4.96061999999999);
#848=EDGE_CURVE('E262',#528,#536,#847,.T.);
#849=ORIENTED_EDGE('',*,*,#848,.T.);
#850=ORIENTED_EDGE('',*,*,#537,.F.);
#851=EDGE_LOOP('',(#849,#850));
#852=FACE_BOUND('',#851,.T.);
#853=ADVANCED_FACE('F401',(#852),#842,.F.);
#854=EDGE_CURVE('E63',#471,#473,#847,.T.);
#855=ORIENTED_EDGE('',*,*,#854,.T.);
#856=ORIENTED_EDGE('',*,*,#474,.F.);
#857=EDGE_LOOP('',(#855,#856));
#858=FACE_BOUND('',#857,.T.);
#859=ADVANCED_FACE('F398',(#858),#842,.F.);
#860=CARTESIAN_POINT('',(26.924,53.34,0.));
#861=DIRECTION('',(1.,0.,0.));
#862=DIRECTION('',(0.,0.,-1.));
#863=AXIS2_PLACEMENT_3D('',#860,#861,#862);
#864=CYLINDRICAL_SURFACE('',#863,4.96061999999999);
#865=ORIENTED_EDGE('',*,*,#739,.T.);
#866=EDGE_LOOP('',(#865));
#867=FACE_BOUND('',#866,.T.);
#868=ORIENTED_EDGE('',*,*,#854,.F.);
#869=ORIENTED_EDGE('',*,*,#590,.F.);
#870=ORIENTED_EDGE('',*,*,#848,.F.);
#871=ORIENTED_EDGE('',*,*,#529,.F.);
#872=EDGE_LOOP('',(#868,#869,#870,#871));
#873=FACE_BOUND('',#872,.T.);
#874=ADVANCED_FACE('F392',(#867,#873),#864,.F.);
#875=CARTESIAN_POINT('',(16.8402,66.04,16.8867242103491));
#876=DIRECTION('',(0.,1.,0.));
#877=DIRECTION('',(0.,0.,1.));
#878=AXIS2_PLACEMENT_3D('',#875,#876,#877);
#879=CYLINDRICAL_SURFACE('',#878,1.89864999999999);
#880=ORIENTED_EDGE('',*,*,#382,.F.);
#881=EDGE_LOOP('',(#880));
#882=FACE_BOUND('',#881,.T.);
#883=ORIENTED_EDGE('',*,*,#64,.T.);
#884=EDGE_LOOP('',(#883));
#885=FACE_BOUND('',#884,.T.);
#886=ADVANCED_FACE('F397',(#882,#885),#879,.F.);
#887=CARTESIAN_POINT('',(-16.8402,66.04,-16.8353752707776));
#888=DIRECTION('',(0.,1.,0.));
#889=DIRECTION('',(0.,0.,1.));
#890=AXIS2_PLACEMENT_3D('',#887,#888,#889);
#891=CYLINDRICAL_SURFACE('',#890,1.89864999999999);
#892=ORIENTED_EDGE('',*,*,#371,.F.);
#893=EDGE_LOOP('',(#892));
#894=FACE_BOUND('',#893,.T.);
#895=ORIENTED_EDGE('',*,*,#53,.T.);
#896=EDGE_LOOP('',(#895));
#897=FACE_BOUND('',#896,.T.);
#898=ADVANCED_FACE('F582',(#894,#897),#891,.F.);
#899=CARTESIAN_POINT('',(-16.8402,66.04,16.8353752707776));
#900=DIRECTION('',(0.,1.,0.));
#901=DIRECTION('',(0.,0.,1.));
#902=AXIS2_PLACEMENT_3D('',#899,#900,#901);
#903=CYLINDRICAL_SURFACE('',#902,2.70509999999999);
#904=ORIENTED_EDGE('',*,*,#360,.F.);
#905=EDGE_LOOP('',(#904));
#906=FACE_BOUND('',#905,.T.);
#907=ORIENTED_EDGE('',*,*,#42,.T.);
#908=EDGE_LOOP('',(#907));
#909=FACE_BOUND('',#908,.T.);
#910=ADVANCED_FACE('F591',(#906,#909),#903,.F.);
#911=CARTESIAN_POINT('',(16.8402,66.04,-16.8867242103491));
#912=DIRECTION('',(0.,1.,0.));
#913=DIRECTION('',(0.,0.,1.));
#914=AXIS2_PLACEMENT_3D('',#911,#912,#913);
#915=CYLINDRICAL_SURFACE('',#914,2.70509999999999);
#916=ORIENTED_EDGE('',*,*,#349,.F.);
#917=EDGE_LOOP('',(#916));
#918=FACE_BOUND('',#917,.T.);
#919=ORIENTED_EDGE('',*,*,#31,.T.);
#920=EDGE_LOOP('',(#919));
#921=FACE_BOUND('',#920,.T.);
#922=ADVANCED_FACE('F607',(#918,#921),#915,.F.);
#923=CARTESIAN_POINT('',(0.,0.,9.525));
#924=DIRECTION('',(0.,-1.,0.));
#925=DIRECTION('',(0.,0.,-1.));
#926=AXIS2_PLACEMENT_3D('',#923,#924,#925);
#927=CYLINDRICAL_SURFACE('',#926,10.5);
#928=CARTESIAN_POINT('',(0.,0.253999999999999,9.525));
#929=DIRECTION('',(0.,-1.,0.));
#930=DIRECTION('',(0.,0.,-1.));
#931=AXIS2_PLACEMENT_3D('',#928,#929,#930);
#932=CIRCLE('',#931,10.5);
#933=CARTESIAN_POINT('',(4.41863949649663,0.253999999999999,0.));
#934=VERTEX_POINT('',#933);
#935=CARTESIAN_POINT('',(-4.41863949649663,0.253999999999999,0.));
#936=VERTEX_POINT('',#935);
#937=EDGE_CURVE('E229',#934,#936,#932,.T.);
#938=ORIENTED_EDGE('',*,*,#937,.F.);
#939=DIRECTION('',(0.,-1.,0.));
#940=VECTOR('',#939,1.);
#941=CARTESIAN_POINT('',(4.41863949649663,0.126999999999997,0.));
#942=LINE('',#941,#940);
#943=EDGE_CURVE('E205',#934,#330,#942,.T.);
#944=ORIENTED_EDGE('',*,*,#943,.T.);
#945=ORIENTED_EDGE('',*,*,#338,.T.);
#946=DIRECTION('',(0.,-1.,0.));
#947=VECTOR('',#946,1.);
#948=CARTESIAN_POINT('',(-4.41863949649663,0.126999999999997,0.));
#949=LINE('',#948,#947);
#950=EDGE_CURVE('E202',#328,#936,#949,.F.);
#951=ORIENTED_EDGE('',*,*,#950,.T.);
#952=EDGE_LOOP('',(#938,#944,#945,#951));
#953=FACE_BOUND('',#952,.T.);
#954=ADVANCED_FACE('F617',(#953),#927,.F.);
#955=CARTESIAN_POINT('',(-6.225,0.253999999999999,9.525));
#956=DIRECTION('',(0.,1.,0.));
#957=DIRECTION('',(0.,0.,1.));
#958=AXIS2_PLACEMENT_3D('',#955,#956,#957);
#959=PLANE('',#958);
#960=CARTESIAN_POINT('',(0.,0.253999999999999,9.525));
#961=DIRECTION('',(0.,-1.,0.));
#962=DIRECTION('',(0.,0.,-1.));
#963=AXIS2_PLACEMENT_3D('',#960,#961,#962);
#964=CIRCLE('',#963,6.225);
#965=CARTESIAN_POINT('',(0.,0.253999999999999,3.3));
#966=VERTEX_POINT('',#965);
#967=EDGE_CURVE('E226',#966,#966,#964,.T.);
#968=ORIENTED_EDGE('',*,*,#967,.F.);
#969=EDGE_LOOP('',(#968));
#970=FACE_BOUND('',#969,.T.);
#971=ORIENTED_EDGE('',*,*,#937,.T.);
#972=CARTESIAN_POINT('',(0.,0.253999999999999,-9.525));
#973=DIRECTION('',(0.,-1.,0.));
#974=DIRECTION('',(0.,0.,-1.));
#975=AXIS2_PLACEMENT_3D('',#972,#973,#974);
#976=CIRCLE('',#975,10.5);
#977=EDGE_CURVE('E55',#936,#934,#976,.T.);
#978=ORIENTED_EDGE('',*,*,#977,.T.);
#979=EDGE_LOOP('',(#971,#978));
#980=FACE_BOUND('',#979,.T.);
#981=CARTESIAN_POINT('',(0.,0.253999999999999,-9.525));
#982=DIRECTION('',(0.,-1.,0.));
#983=DIRECTION('',(0.,0.,-1.));
#984=AXIS2_PLACEMENT_3D('',#981,#982,#983);
#985=CIRCLE('',#984,6.225);
#986=CARTESIAN_POINT('',(0.,0.253999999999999,-15.75));
#987=VERTEX_POINT('',#986);
#988=EDGE_CURVE('E196',#987,#987,#985,.T.);
#989=ORIENTED_EDGE('',*,*,#988,.F.);
#990=EDGE_LOOP('',(#989));
#991=FACE_BOUND('',#990,.T.);
#992=ADVANCED_FACE('F631',(#970,#980,#991),#959,.F.);
#993=CARTESIAN_POINT('',(0.,0.507999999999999,9.525));
#994=DIRECTION('',(0.,-1.,0.));
#995=DIRECTION('',(0.,0.,-1.));
#996=AXIS2_PLACEMENT_3D('',#993,#994,#995);
#997=TOROIDAL_SURFACE('',#996,6.225,0.254000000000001);
#998=CARTESIAN_POINT('',(0.,0.45519043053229,9.525));
#999=DIRECTION('',(0.,-1.,0.));
#1000=DIRECTION('',(0.,0.,-1.));
#1001=AXIS2_PLACEMENT_3D('',#998,#999,#1000);
#1002=CIRCLE('',#1001,5.97655050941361);
#1003=CARTESIAN_POINT('',(0.,0.45519043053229,3.54844949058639));
#1004=VERTEX_POINT('',#1003);
#1005=EDGE_CURVE('E223',#1004,#1004,#1002,.T.);
#1006=ORIENTED_EDGE('',*,*,#1005,.F.);
#1007=EDGE_LOOP('',(#1006));
#1008=FACE_BOUND('',#1007,.T.);
#1009=ORIENTED_EDGE('',*,*,#967,.T.);
#1010=EDGE_LOOP('',(#1009));
#1011=FACE_BOUND('',#1010,.T.);
#1012=ADVANCED_FACE('F625',(#1008,#1011),#997,.T.);
#1013=CARTESIAN_POINT('',(0.,0.45519043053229,9.525));
#1014=DIRECTION('',(0.,-1.,0.));
#1015=DIRECTION('',(0.,0.,-1.));
#1016=AXIS2_PLACEMENT_3D('',#1013,#1014,#1015);
#1017=CONICAL_SURFACE('',#1016,5.97655050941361,0.209439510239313);
#1018=CARTESIAN_POINT('',(0.,2.854,9.525));
#1019=DIRECTION('',(0.,-1.,0.));
#1020=DIRECTION('',(0.,0.,-1.));
#1021=AXIS2_PLACEMENT_3D('',#1018,#1019,#1020);
#1022=CIRCLE('',#1021,5.46666779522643);
#1023=CARTESIAN_POINT('',(0.,2.854,4.05833220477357));
#1024=VERTEX_POINT('',#1023);
#1025=EDGE_CURVE('E220',#1024,#1024,#1022,.T.);
#1026=ORIENTED_EDGE('',*,*,#1025,.F.);
#1027=EDGE_LOOP('',(#1026));
#1028=FACE_BOUND('',#1027,.T.);
#1029=ORIENTED_EDGE('',*,*,#1005,.T.);
#1030=EDGE_LOOP('',(#1029));
#1031=FACE_BOUND('',#1030,.T.);
#1032=ADVANCED_FACE('F630',(#1028,#1031),#1017,.F.);
#1033=CARTESIAN_POINT('',(0.,2.854,9.525));
#1034=DIRECTION('',(0.,-1.,0.));
#1035=DIRECTION('',(0.,0.,-1.));
#1036=AXIS2_PLACEMENT_3D('',#1033,#1034,#1035);
#1037=CONICAL_SURFACE('',#1036,5.46666779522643,0.785398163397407);
#1038=CARTESIAN_POINT('',(0.,2.76441779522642,9.525));
#1039=DIRECTION('',(0.,-1.,0.));
#1040=DIRECTION('',(0.,0.,-1.));
#1041=AXIS2_PLACEMENT_3D('',#1038,#1039,#1040);
#1042=CIRCLE('',#1041,5.55625);
#1043=CARTESIAN_POINT('',(0.,2.76441779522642,3.96875));
#1044=VERTEX_POINT('',#1043);
#1045=EDGE_CURVE('E217',#1044,#1044,#1042,.T.);
#1046=ORIENTED_EDGE('',*,*,#1045,.F.);
#1047=EDGE_LOOP('',(#1046));
#1048=FACE_BOUND('',#1047,.T.);
#1049=ORIENTED_EDGE('',*,*,#1025,.T.);
#1050=EDGE_LOOP('',(#1049));
#1051=FACE_BOUND('',#1050,.T.);
#1052=ADVANCED_FACE('F643',(#1048,#1051),#1037,.T.);
#1053=CARTESIAN_POINT('',(0.,0.,9.525));
#1054=DIRECTION('',(0.,-1.,0.));
#1055=DIRECTION('',(0.,0.,-1.));
#1056=AXIS2_PLACEMENT_3D('',#1053,#1054,#1055);
#1057=CYLINDRICAL_SURFACE('',#1056,5.55625);
#1058=CARTESIAN_POINT('',(0.,11.754,9.525));
#1059=DIRECTION('',(0.,-1.,0.));
#1060=DIRECTION('',(0.,0.,-1.));
#1061=AXIS2_PLACEMENT_3D('',#1058,#1059,#1060);
#1062=CIRCLE('',#1061,5.55625);
#1063=CARTESIAN_POINT('',(0.,11.754,3.96875));
#1064=VERTEX_POINT('',#1063);
#1065=EDGE_CURVE('E214',#1064,#1064,#1062,.T.);
#1066=ORIENTED_EDGE('',*,*,#1065,.F.);
#1067=EDGE_LOOP('',(#1066));
#1068=FACE_BOUND('',#1067,.T.);
#1069=ORIENTED_EDGE('',*,*,#1045,.T.);
#1070=EDGE_LOOP('',(#1069));
#1071=FACE_BOUND('',#1070,.T.);
#1072=ADVANCED_FACE('F654',(#1068,#1071),#1057,.F.);
#1073=CARTESIAN_POINT('',(-4.96062,11.754,9.525));
#1074=DIRECTION('',(0.,1.,0.));
#1075=DIRECTION('',(0.,0.,1.));
#1076=AXIS2_PLACEMENT_3D('',#1073,#1074,#1075);
#1077=PLANE('',#1076);
#1078=CARTESIAN_POINT('',(0.,11.754,9.525));
#1079=DIRECTION('',(0.,-1.,0.));
#1080=DIRECTION('',(0.,0.,-1.));
#1081=AXIS2_PLACEMENT_3D('',#1078,#1079,#1080);
#1082=CIRCLE('',#1081,4.96062);
#1083=CARTESIAN_POINT('',(0.,11.754,4.56438));
#1084=VERTEX_POINT('',#1083);
#1085=EDGE_CURVE('E211',#1084,#1084,#1082,.T.);
#1086=ORIENTED_EDGE('',*,*,#1085,.F.);
#1087=EDGE_LOOP('',(#1086));
#1088=FACE_BOUND('',#1087,.T.);
#1089=ORIENTED_EDGE('',*,*,#1065,.T.);
#1090=EDGE_LOOP('',(#1089));
#1091=FACE_BOUND('',#1090,.T.);
#1092=ADVANCED_FACE('F665',(#1088,#1091),#1077,.F.);
#1093=CARTESIAN_POINT('',(0.,0.,9.525));
#1094=DIRECTION('',(0.,-1.,0.));
#1095=DIRECTION('',(0.,0.,-1.));
#1096=AXIS2_PLACEMENT_3D('',#1093,#1094,#1095);
#1097=CYLINDRICAL_SURFACE('',#1096,4.96062);
#1098=CARTESIAN_POINT('',(0.,14.254,9.525));
#1099=DIRECTION('',(0.,-1.,0.));
#1100=DIRECTION('',(0.,0.,-1.));
#1101=AXIS2_PLACEMENT_3D('',#1098,#1099,#1100);
#1102=CIRCLE('',#1101,4.96062);
#1103=CARTESIAN_POINT('',(0.,14.254,4.56438));
#1104=VERTEX_POINT('',#1103);
#1105=EDGE_CURVE('E208',#1104,#1104,#1102,.T.);
#1106=ORIENTED_EDGE('',*,*,#1105,.F.);
#1107=EDGE_LOOP('',(#1106));
#1108=FACE_BOUND('',#1107,.T.);
#1109=ORIENTED_EDGE('',*,*,#1085,.T.);
#1110=EDGE_LOOP('',(#1109));
#1111=FACE_BOUND('',#1110,.T.);
#1112=ADVANCED_FACE('F676',(#1108,#1111),#1097,.F.);
#1113=CARTESIAN_POINT('',(0.,14.254,9.525));
#1114=DIRECTION('',(0.,-1.,0.));
#1115=DIRECTION('',(0.,0.,-1.));
#1116=AXIS2_PLACEMENT_3D('',#1113,#1114,#1115);
#1117=CONICAL_SURFACE('',#1116,4.96062,1.02974425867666);
#1118=CARTESIAN_POINT('',(0.,17.2346412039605,9.525));
#1119=VERTEX_POINT('',#1118);
#1120=VERTEX_LOOP('',#1119);
#1121=FACE_BOUND('',#1120,.T.);
#1122=ORIENTED_EDGE('',*,*,#1105,.T.);
#1123=EDGE_LOOP('',(#1122));
#1124=FACE_BOUND('',#1123,.T.);
#1125=ADVANCED_FACE('F687',(#1121,#1124),#1117,.F.);
#1126=CARTESIAN_POINT('',(0.,0.,-9.525));
#1127=DIRECTION('',(0.,-1.,0.));
#1128=DIRECTION('',(0.,0.,-1.));
#1129=AXIS2_PLACEMENT_3D('',#1126,#1127,#1128);
#1130=CYLINDRICAL_SURFACE('',#1129,10.5);
#1131=ORIENTED_EDGE('',*,*,#977,.F.);
#1132=ORIENTED_EDGE('',*,*,#950,.F.);
#1133=ORIENTED_EDGE('',*,*,#331,.T.);
#1134=ORIENTED_EDGE('',*,*,#943,.F.);
#1135=EDGE_LOOP('',(#1131,#1132,#1133,#1134));
#1136=FACE_BOUND('',#1135,.T.);
#1137=ADVANCED_FACE('F698',(#1136),#1130,.F.);
#1138=CARTESIAN_POINT('',(0.,0.507999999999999,-9.525));
#1139=DIRECTION('',(0.,-1.,0.));
#1140=DIRECTION('',(0.,0.,-1.));
#1141=AXIS2_PLACEMENT_3D('',#1138,#1139,#1140);
#1142=TOROIDAL_SURFACE('',#1141,6.225,0.254000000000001);
#1143=CARTESIAN_POINT('',(0.,0.45519043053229,-9.525));
#1144=DIRECTION('',(0.,-1.,0.));
#1145=DIRECTION('',(0.,0.,-1.));
#1146=AXIS2_PLACEMENT_3D('',#1143,#1144,#1145);
#1147=CIRCLE('',#1146,5.97655050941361);
#1148=CARTESIAN_POINT('',(0.,0.45519043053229,-15.5015505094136));
#1149=VERTEX_POINT('',#1148);
#1150=EDGE_CURVE('E193',#1149,#1149,#1147,.T.);
#1151=ORIENTED_EDGE('',*,*,#1150,.F.);
#1152=EDGE_LOOP('',(#1151));
#1153=FACE_BOUND('',#1152,.T.);
#1154=ORIENTED_EDGE('',*,*,#988,.T.);
#1155=EDGE_LOOP('',(#1154));
#1156=FACE_BOUND('',#1155,.T.);
#1157=ADVANCED_FACE('F735',(#1153,#1156),#1142,.T.);
#1158=CARTESIAN_POINT('',(0.,0.45519043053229,-9.525));
#1159=DIRECTION('',(0.,-1.,0.));
#1160=DIRECTION('',(0.,0.,-1.));
#1161=AXIS2_PLACEMENT_3D('',#1158,#1159,#1160);
#1162=CONICAL_SURFACE('',#1161,5.97655050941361,0.209439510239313);
#1163=CARTESIAN_POINT('',(0.,2.854,-9.525));
#1164=DIRECTION('',(0.,-1.,0.));
#1165=DIRECTION('',(0.,0.,-1.));
#1166=AXIS2_PLACEMENT_3D('',#1163,#1164,#1165);
#1167=CIRCLE('',#1166,5.46666779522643);
#1168=CARTESIAN_POINT('',(0.,2.854,-14.9916677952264));
#1169=VERTEX_POINT('',#1168);
#1170=EDGE_CURVE('E190',#1169,#1169,#1167,.T.);
#1171=ORIENTED_EDGE('',*,*,#1170,.F.);
#1172=EDGE_LOOP('',(#1171));
#1173=FACE_BOUND('',#1172,.T.);
#1174=ORIENTED_EDGE('',*,*,#1150,.T.);
#1175=EDGE_LOOP('',(#1174));
#1176=FACE_BOUND('',#1175,.T.);
#1177=ADVANCED_FACE('F746',(#1173,#1176),#1162,.F.);
#1178=CARTESIAN_POINT('',(0.,2.854,-9.525));
#1179=DIRECTION('',(0.,-1.,0.));
#1180=DIRECTION('',(0.,0.,-1.));
#1181=AXIS2_PLACEMENT_3D('',#1178,#1179,#1180);
#1182=CONICAL_SURFACE('',#1181,5.46666779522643,0.785398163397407);
#1183=CARTESIAN_POINT('',(0.,2.76441779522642,-9.525));
#1184=DIRECTION('',(0.,-1.,0.));
#1185=DIRECTION('',(0.,0.,-1.));
#1186=AXIS2_PLACEMENT_3D('',#1183,#1184,#1185);
#1187=CIRCLE('',#1186,5.55625);
#1188=CARTESIAN_POINT('',(0.,2.76441779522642,-15.08125));
#1189=VERTEX_POINT('',#1188);
#1190=EDGE_CURVE('E187',#1189,#1189,#1187,.T.);
#1191=ORIENTED_EDGE('',*,*,#1190,.F.);
#1192=EDGE_LOOP('',(#1191));
#1193=FACE_BOUND('',#1192,.T.);
#1194=ORIENTED_EDGE('',*,*,#1170,.T.);
#1195=EDGE_LOOP('',(#1194));
#1196=FACE_BOUND('',#1195,.T.);
#1197=ADVANCED_FACE('F757',(#1193,#1196),#1182,.T.);
#1198=CARTESIAN_POINT('',(0.,0.,-9.525));
#1199=DIRECTION('',(0.,-1.,0.));
#1200=DIRECTION('',(0.,0.,-1.));
#1201=AXIS2_PLACEMENT_3D('',#1198,#1199,#1200);
#1202=CYLINDRICAL_SURFACE('',#1201,5.55625);
#1203=CARTESIAN_POINT('',(0.,11.754,-9.525));
#1204=DIRECTION('',(0.,-1.,0.));
#1205=DIRECTION('',(0.,0.,-1.));
#1206=AXIS2_PLACEMENT_3D('',#1203,#1204,#1205);
#1207=CIRCLE('',#1206,5.55625);
#1208=CARTESIAN_POINT('',(0.,11.754,-15.08125));
#1209=VERTEX_POINT('',#1208);
#1210=EDGE_CURVE('E182',#1209,#1209,#1207,.T.);
#1211=ORIENTED_EDGE('',*,*,#1210,.F.);
#1212=EDGE_LOOP('',(#1211));
#1213=FACE_BOUND('',#1212,.T.);
#1214=ORIENTED_EDGE('',*,*,#1190,.T.);
#1215=EDGE_LOOP('',(#1214));
#1216=FACE_BOUND('',#1215,.T.);
#1217=ADVANCED_FACE('F768',(#1213,#1216),#1202,.F.);
#1218=CARTESIAN_POINT('',(-4.96062,11.754,-9.525));
#1219=DIRECTION('',(0.,1.,0.));
#1220=DIRECTION('',(0.,0.,1.));
#1221=AXIS2_PLACEMENT_3D('',#1218,#1219,#1220);
#1222=PLANE('',#1221);
#1223=CARTESIAN_POINT('',(0.,11.754,-9.525));
#1224=DIRECTION('',(0.,-1.,0.));
#1225=DIRECTION('',(0.,0.,-1.));
#1226=AXIS2_PLACEMENT_3D('',#1223,#1224,#1225);
#1227=CIRCLE('',#1226,4.96062);
#1228=CARTESIAN_POINT('',(0.,11.754,-14.48562));
#1229=VERTEX_POINT('',#1228);
#1230=EDGE_CURVE('E179',#1229,#1229,#1227,.T.);
#1231=ORIENTED_EDGE('',*,*,#1230,.F.);
#1232=EDGE_LOOP('',(#1231));
#1233=FACE_BOUND('',#1232,.T.);
#1234=ORIENTED_EDGE('',*,*,#1210,.T.);
#1235=EDGE_LOOP('',(#1234));
#1236=FACE_BOUND('',#1235,.T.);
#1237=ADVANCED_FACE('F779',(#1233,#1236),#1222,.F.);
#1238=CARTESIAN_POINT('',(0.,0.,-9.525));
#1239=DIRECTION('',(0.,-1.,0.));
#1240=DIRECTION('',(0.,0.,-1.));
#1241=AXIS2_PLACEMENT_3D('',#1238,#1239,#1240);
#1242=CYLINDRICAL_SURFACE('',#1241,4.96062);
#1243=CARTESIAN_POINT('',(0.,14.254,-9.525));
#1244=DIRECTION('',(0.,-1.,0.));
#1245=DIRECTION('',(0.,0.,-1.));
#1246=AXIS2_PLACEMENT_3D('',#1243,#1244,#1245);
#1247=CIRCLE('',#1246,4.96062);
#1248=CARTESIAN_POINT('',(0.,14.254,-14.48562));
#1249=VERTEX_POINT('',#1248);
#1250=EDGE_CURVE('E177',#1249,#1249,#1247,.T.);
#1251=ORIENTED_EDGE('',*,*,#1250,.F.);
#1252=EDGE_LOOP('',(#1251));
#1253=FACE_BOUND('',#1252,.T.);
#1254=ORIENTED_EDGE('',*,*,#1230,.T.);
#1255=EDGE_LOOP('',(#1254));
#1256=FACE_BOUND('',#1255,.T.);
#1257=ADVANCED_FACE('F173',(#1253,#1256),#1242,.F.);
#1258=CARTESIAN_POINT('',(0.,14.254,-9.525));
#1259=DIRECTION('',(0.,-1.,0.));
#1260=DIRECTION('',(0.,0.,-1.));
#1261=AXIS2_PLACEMENT_3D('',#1258,#1259,#1260);
#1262=CONICAL_SURFACE('',#1261,4.96062,1.02974425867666);
#1263=CARTESIAN_POINT('',(0.,17.2346412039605,-9.525));
#1264=VERTEX_POINT('',#1263);
#1265=VERTEX_LOOP('',#1264);
#1266=FACE_BOUND('',#1265,.T.);
#1267=ORIENTED_EDGE('',*,*,#1250,.T.);
#1268=EDGE_LOOP('',(#1267));
#1269=FACE_BOUND('',#1268,.T.);
#1270=ADVANCED_FACE('F170',(#1266,#1269),#1262,.F.);
#1271=CLOSED_SHELL('',(#183,#223,#254,#285,#316,#420,#440,#460,#608,#617,#629,#641,#668,#695,
#726,#761,#785,#813,#825,#837,#853,#859,#874,#886,#898,#910,#922,#954,#992,#1012,#1032,#1052,
#1072,#1092,#1112,#1125,#1137,#1157,#1177,#1197,#1217,#1237,#1257,#1270));
#1272=MANIFOLD_SOLID_BREP('B2',#1271);
#1273=ADVANCED_BREP_SHAPE_REPRESENTATION('',(#18,#1272),#14);
#1274=SHAPE_DEFINITION_REPRESENTATION(#9,#1273);
ENDSEC;
END-ISO-10303-21;
